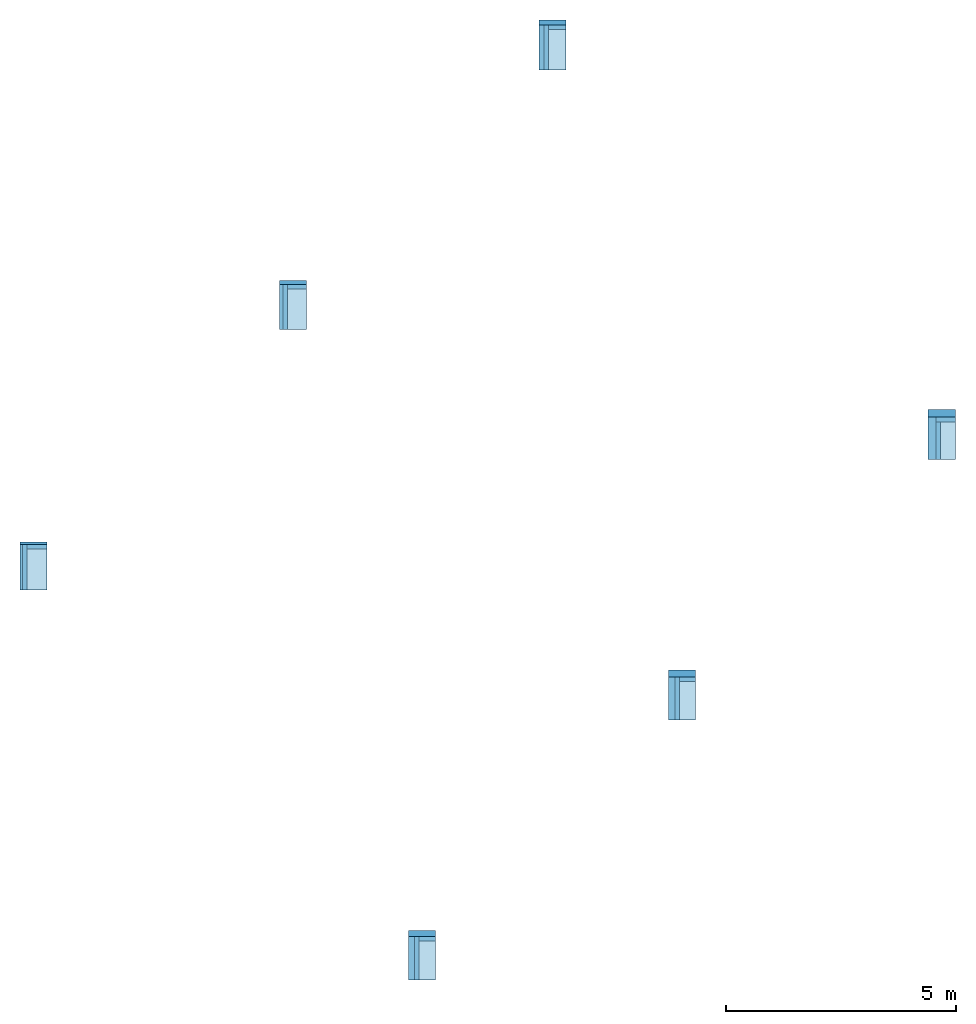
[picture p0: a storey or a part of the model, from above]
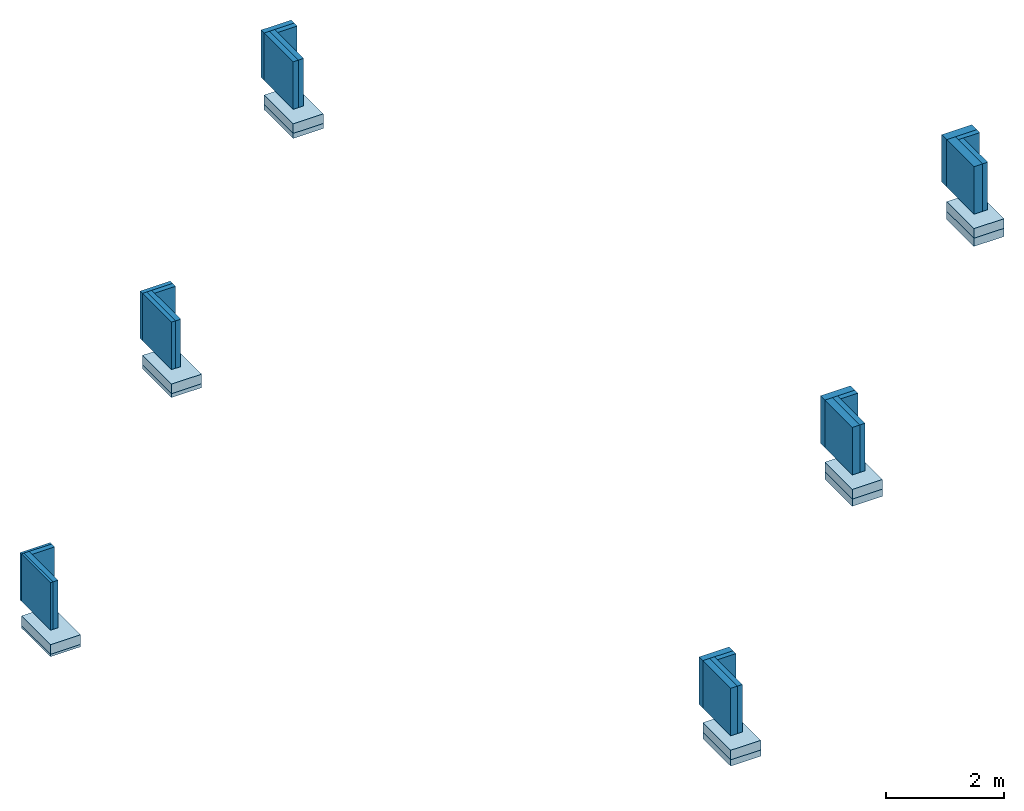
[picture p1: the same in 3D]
Properties of the parts of a building model (IFC2X3), part 2 of 2

# IfcWallStandardCase: Basic Wall:NLRS_42_WA_Heraklith Herafoam 105x985x590mm, Basic Wall:NLRS_42_WA_Heraklith Herafoam 105x985x590mm:925849
Type - Identity Data - Type Image: Raster image: Heraklith Herafoam.jpg; Assembly Code: 42.10; brandweerstand: n.v.t; Description: Herafoam - 105mm; DoP: 4010_HERAFOAM; email: customerservice.nl@knaufinsulation.com; geluidsabsorbtie: 0,30; Manufacturer: Knauf Insulation B.V.; Model: Heraklith® | Herafoam is een houtwolcementpaneel gecombineerd met een PIR-plaat.; NLRS_C_Code_Brandklasse: B-s1,d0; NLRS_C_content_creator: Cadix; NLRS_C_content_versie: V1.0; phone: +31(0)162-421245; product URL: https://heraklith.nl/Heraklith-houtwolcementplaten/herafoam; Type Name: NLRS_42_WA_Heraklith Herafoam 105x985x590mm; URL: www.heraklith.nl; warmteweerstand: 4,10 (m2.K/W)
Type - Other - Category: Walls; Family Name: Basic Wall
Classification: 42.10 (Uniformat)
BaseQuantities - Height: 985 mm; Length: 985 mm; Width: 105 mm; GrossFootprintArea: 0.103425 m2; GrossSideArea: 0.970225 m2; GrossVolume: 0.101874 m3
Constraints - Related to Mass: no; Room Bounding: yes; Base Constraint: Level: 00 begane grond; Base Extension Distance: 0 mm; Base is Attached: no; Base Offset: 0 mm; Location Line: Wall Centerline; Top Constraint: Level: 01 eerste verdieping; Top Extension Distance: 0 mm; Top is Attached: no; Top Offset: 0 mm; Unconnected Height: 985 mm
Dimensions - Area: 0.970225 m2; Length: 985 mm; Volume: 0.101874 m3
Other - Family: Basic Wall: NLRS_42_WA_Heraklith Herafoam 105x985x590mm; Family and Type: Basic Wall: NLRS_42_WA_Heraklith Herafoam 105x985x590mm; Type: Basic Wall: NLRS_42_WA_Heraklith Herafoam 105x985x590mm; Type Id: Basic Wall: NLRS_42_WA_Heraklith Herafoam 105x985x590mm
Phasing - Phase Created: 1
Structural - Enable Analytical Model: no; Structural: no; Structural Usage: Non-bearing
Pset_WallCommon - LoadBearing: no; ExtendToStructure: no; IsExternal: no; Reference: NLRS_42_WA_Heraklith Herafoam 105x985x590mm; ThermalTransmittance: 0.22577 kg/K/s3
Pset_ManufacturerTypeInformation - Manufacturer: Knauf Insulation B.V.

# IfcWallStandardCase: Basic Wall:NLRS_42_WA_Heraklith Herafoam 130x985x590mm, Basic Wall:NLRS_42_WA_Heraklith Herafoam 130x985x590mm:926114
In: 00 begane grond
Type - PredefinedType: STANDARD; Material: Heraklith® | Herafoam - PIR (0,0215) 80 mm, Heraklith® | Herafoam - PIR (0,0275) 40 mm, Heraklith® | Herafoam - Houtwollaag - 985x590mm 10 mm
Type - Analytical Properties - Roughness: 1; Absorptance: 0.1; Heat Transfer Coefficient (U): 0.179673; Thermal mass: 810; Thermal Resistance (R): 5.56566
Type - Construction - Function: Interior; Wrapping at Inserts: Do not wrap; Width: 130 mm
Type - Data - CE-codering: WW-C2 PU-EN13168-L2-W1-S1-T1-P1-CS(10/Y)150-Cl1; Chloride gehalte: Cl1; Druksterkte kPa: 150; gewicht KG/M2: 10.1; kleur: standaard naturel optie: Wit (RAL9003) / RAL; pallet m2: 9.3 m2; panelen per pallet: 16; Randafwerking: Houtwol: Facet: 5mm; Randafwerking: Isolatie: tand en groef; Tolerantie: Breedte (W): (W1) +3/-3; Tolerantie: Dikte (T): (T1) +3/-2; Tolerantie: Haaksheid (S): (S1) ≤4; Tolerantie: Lengte (L): (L2) +3/-5; Tolerantie: Vlakheid (P): (P1) ≤6; vezelbreedte: standaard 2mm optie: 1mm
Type - Graphics - Coarse Scale Fill Color: 0; Coarse Scale Fill Pattern: Solid fill
Type - Identity Data - Type Image: Raster image: Heraklith Herafoam.jpg; Assembly Code: 42.10; brandweerstand: n.v.t; Description: Herafoam - 130mm; DoP: 4010_HERAFOAM; email: customerservice.nl@knaufinsulation.com; geluidsabsorbtie: 0,30; Manufacturer: Knauf Insulation B.V.; Model: Heraklith® | Herafoam is een houtwolcementpaneel gecombineerd met een PIR-plaat.; NLRS_C_Code_Brandklasse: B-s1,d0; NLRS_C_content_creator: Cadix; NLRS_C_content_versie: V1.0; phone: +31(0)162-421245; product URL: https://heraklith.nl/Heraklith-houtwolcementplaten/herafoam; Type Name: NLRS_42_WA_Heraklith Herafoam 130x985x590mm; URL: www.heraklith.nl; warmteweerstand: 5,25 (m2.K/W)
Type - Other - Category: Walls; Family Name: Basic Wall
Classification: 42.10 (Uniformat)
BaseQuantities - Height: 985 mm; Length: 945 mm; Width: 130 mm; GrossFootprintArea: 0.12285 m2; GrossSideArea: 0.930825 m2; GrossVolume: 0.121007 m3
Constraints - Related to Mass: no; Room Bounding: yes; Base Constraint: Level: 00 begane grond; Base Extension Distance: 0 mm; Base is Attached: no; Base Offset: 0 mm; Location Line: Wall Centerline; Top Constraint: Level: 01 eerste verdieping; Top Extension Distance: 0 mm; Top is Attached: no; Top Offset: 0 mm; Unconnected Height: 985 mm
Dimensions - Area: 0.930825 m2; Length: 1010 mm; Volume: 0.121007 m3
Other - Family: Basic Wall: NLRS_42_WA_Heraklith Herafoam 130x985x590mm; Family and Type: Basic Wall: NLRS_42_WA_Heraklith Herafoam 130x985x590mm; Type: Basic Wall: NLRS_42_WA_Heraklith Herafoam 130x985x590mm; Type Id: Basic Wall: NLRS_42_WA_Heraklith Herafoam 130x985x590mm
Phasing - Phase Created: 1
Structural - Enable Analytical Model: no; Structural: no; Structural Usage: Non-bearing
Pset_WallCommon - LoadBearing: no; ExtendToStructure: no; IsExternal: no; Reference: NLRS_42_WA_Heraklith Herafoam 130x985x590mm; ThermalTransmittance: 0.179673 kg/K/s3
Pset_ManufacturerTypeInformation - Manufacturer: Knauf Insulation B.V.

# IfcWallStandardCase: Basic Wall:NLRS_42_WA_Heraklith Herafoam 150x985x590mm, Basic Wall:NLRS_42_WA_Heraklith Herafoam 150x985x590mm:926746
In: 00 begane grond
Type - PredefinedType: STANDARD; Material: Heraklith® | Herafoam - PIR (0,0215) 100 mm, Heraklith® | Herafoam - PIR (0,0275) 40 mm, Heraklith® | Herafoam - Houtwollaag - 985x590mm 10 mm
Type - Analytical Properties - Roughness: 1; Absorptance: 0.1; Heat Transfer Coefficient (U): 0.154446; Thermal mass: 870; Thermal Resistance (R): 6.47475
Type - Construction - Function: Interior; Wrapping at Inserts: Do not wrap; Width: 150 mm
Type - Data - CE-codering: WW-C2 PU-EN13168-L2-W1-S1-T1-P1-CS(10/Y)150-Cl1; Chloride gehalte: Cl1; Druksterkte kPa: 150; gewicht KG/M2: 10.7; kleur: standaard naturel optie: Wit (RAL9003) / RAL; pallet m2: 8.14 m2; panelen per pallet: 14; Randafwerking: Houtwol: Facet: 5mm; Randafwerking: Isolatie: tand en groef; Tolerantie: Breedte (W): (W1) +3/-3; Tolerantie: Dikte (T): (T1) +3/-2; Tolerantie: Haaksheid (S): (S1) ≤4; Tolerantie: Lengte (L): (L2) +3/-5; Tolerantie: Vlakheid (P): (P1) ≤6; vezelbreedte: standaard 2mm optie: 1mm
Type - Graphics - Coarse Scale Fill Color: 0; Coarse Scale Fill Pattern: Solid fill
Type - Identity Data - Type Image: Raster image: Heraklith Herafoam.jpg; Assembly Code: 42.10; brandweerstand: n.v.t; Description: Herafoam - 150mm; DoP: 4010_HERAFOAM; email: customerservice.nl@knaufinsulation.com; geluidsabsorbtie: 0,30; Manufacturer: Knauf Insulation B.V.; Model: Heraklith® | Herafoam is een houtwolcementpaneel gecombineerd met een PIR-plaat.; NLRS_C_Code_Brandklasse: B-s1,d0; NLRS_C_content_creator: Cadix; NLRS_C_content_versie: V1.0; phone: +31(0)162-421245; product URL: https://heraklith.nl/Heraklith-houtwolcementplaten/herafoam; Type Name: NLRS_42_WA_Heraklith Herafoam 150x985x590mm; URL: www.heraklith.nl; warmteweerstand: 6,20 (m2.K/W)
Type - Other - Category: Walls; Family Name: Basic Wall
Classification: 42.10 (Uniformat)
BaseQuantities - Height: 985 mm; Length: 935 mm; Width: 150 mm; GrossFootprintArea: 0.14025 m2; GrossSideArea: 0.920975 m2; GrossVolume: 0.138146 m3
Constraints - Related to Mass: no; Room Bounding: yes; Base Constraint: Level: 00 begane grond; Base Extension Distance: 0 mm; Base is Attached: no; Base Offset: 0 mm; Location Line: Wall Centerline; Top Constraint: Level: 01 eerste verdieping; Top Extension Distance: 0 mm; Top is Attached: no; Top Offset: 0 mm; Unconnected Height: 985 mm
Dimensions - Area: 0.920975 m2; Length: 1010 mm; Volume: 0.138146 m3
Other - Family: Basic Wall: NLRS_42_WA_Heraklith Herafoam 150x985x590mm; Family and Type: Basic Wall: NLRS_42_WA_Heraklith Herafoam 150x985x590mm; Type: Basic Wall: NLRS_42_WA_Heraklith Herafoam 150x985x590mm; Type Id: Basic Wall: NLRS_42_WA_Heraklith Herafoam 150x985x590mm
Phasing - Phase Created: 1
Structural - Enable Analytical Model: no; Structural: no; Structural Usage: Non-bearing
Pset_WallCommon - LoadBearing: no; ExtendToStructure: no; IsExternal: no; Reference: NLRS_42_WA_Heraklith Herafoam 150x985x590mm; ThermalTransmittance: 0.154446 kg/K/s3
Pset_ManufacturerTypeInformation - Manufacturer: Knauf Insulation B.V.

# IfcWallStandardCase: Basic Wall:NLRS_42_WA_Heraklith Herafoam 170x985x590mm, Basic Wall:NLRS_42_WA_Heraklith Herafoam 170x985x590mm:926985
In: 00 begane grond
Type - PredefinedType: STANDARD; Material: Heraklith® | Herafoam - PIR (0,0215) 120 mm, Heraklith® | Herafoam - PIR (0,0275) 40 mm, Heraklith® | Herafoam - Houtwollaag - 985x590mm 10 mm
Type - Analytical Properties - Roughness: 1; Absorptance: 0.1; Heat Transfer Coefficient (U): 0.135431; Thermal mass: 930; Thermal Resistance (R): 7.38384
Type - Construction - Function: Interior; Wrapping at Inserts: Do not wrap; Width: 170 mm
Type - Data - CE-codering: WW-C2 PU-EN13168-L2-W1-S1-T1-P1-CS(10/Y)150-Cl1; Chloride gehalte: Cl1; Druksterkte kPa: 150; gewicht KG/M2: 11.3; kleur: standaard naturel optie: Wit (RAL9003) / RAL; pallet m2: 6.97 m2; panelen per pallet: 12; Randafwerking: Houtwol: Facet: 5mm; Randafwerking: Isolatie: tand en groef; Tolerantie: Breedte (W): (W1) +3/-3; Tolerantie: Dikte (T): (T1) +3/-2; Tolerantie: Haaksheid (S): (S1) ≤4; Tolerantie: Lengte (L): (L2) +3/-5; Tolerantie: Vlakheid (P): (P1) ≤6; vezelbreedte: standaard 2mm optie: 1mm
Type - Graphics - Coarse Scale Fill Color: 0; Coarse Scale Fill Pattern: Solid fill
Type - Identity Data - Type Image: Raster image: Heraklith Herafoam.jpg; Assembly Code: 42.10; brandweerstand: n.v.t; Description: Herafoam - 170mm; DoP: 4010_HERAFOAM; email: customerservice.nl@knaufinsulation.com; geluidsabsorbtie: 0,30; Manufacturer: Knauf Insulation B.V.; Model: Heraklith® | Herafoam is een houtwolcementpaneel gecombineerd met een PIR-plaat.; NLRS_C_Code_Brandklasse: B-s1,d0; NLRS_C_content_creator: Cadix; NLRS_C_content_versie: V1.0; phone: +31(0)162-421245; product URL: https://heraklith.nl/Heraklith-houtwolcementplaten/herafoam; Type Name: NLRS_42_WA_Heraklith Herafoam 170x985x590mm; URL: www.heraklith.nl; warmteweerstand: 7,10 (m2.K/W)
Type - Other - Category: Walls; Family Name: Basic Wall
Classification: 42.10 (Uniformat)
BaseQuantities - Height: 985 mm; Length: 925 mm; Width: 170 mm; GrossFootprintArea: 0.15725 m2; GrossSideArea: 0.911125 m2; GrossVolume: 0.154891 m3
Constraints - Related to Mass: no; Room Bounding: yes; Base Constraint: Level: 00 begane grond; Base Extension Distance: 0 mm; Base is Attached: no; Base Offset: 0 mm; Location Line: Wall Centerline; Top Constraint: Level: 01 eerste verdieping; Top Extension Distance: 0 mm; Top is Attached: no; Top Offset: 0 mm; Unconnected Height: 985 mm
Dimensions - Area: 0.911125 m2; Length: 1010 mm; Volume: 0.154891 m3
Other - Family: Basic Wall: NLRS_42_WA_Heraklith Herafoam 170x985x590mm; Family and Type: Basic Wall: NLRS_42_WA_Heraklith Herafoam 170x985x590mm; Type: Basic Wall: NLRS_42_WA_Heraklith Herafoam 170x985x590mm; Type Id: Basic Wall: NLRS_42_WA_Heraklith Herafoam 170x985x590mm
Phasing - Phase Created: 1
Structural - Enable Analytical Model: no; Structural: no; Structural Usage: Non-bearing
Pset_WallCommon - LoadBearing: no; ExtendToStructure: no; IsExternal: no; Reference: NLRS_42_WA_Heraklith Herafoam 170x985x590mm; ThermalTransmittance: 0.135431 kg/K/s3
Pset_ManufacturerTypeInformation - Manufacturer: Knauf Insulation B.V.

# IfcWallStandardCase: Basic Wall:NLRS_42_WA_Heraklith Herafoam 50x985x590mm, Basic Wall:NLRS_42_WA_Heraklith Herafoam 50x985x590mm:922774
In: 00 begane grond
Type - PredefinedType: STANDARD; Material: Heraklith® | Herafoam - PIR (0,0275) 40 mm, Heraklith® | Herafoam - Houtwollaag - 985x590mm 10 mm
Type - Analytical Properties - Roughness: 1; Absorptance: 0.1; Heat Transfer Coefficient (U): 0.518325; Thermal mass: 570; Thermal Resistance (R): 1.92929
Type - Construction - Function: Interior; Width: 50 mm; Wrapping at Inserts: Do not wrap
Type - Data - CE-codering: WW-C2 PU-EN13168-L2-W1-S1-T1-P1-CS(10/Y)150-Cl1; Chloride gehalte: Cl1; Druksterkte kPa: 150; gewicht KG/M2: 7.3; kleur: standaard naturel optie: Wit (RAL9003) / RAL; pallet m2: 25.57 m2; panelen per pallet: 44; Randafwerking: Houtwol: Facet: 5mm; Randafwerking: Isolatie: tand en groef; Tolerantie: Breedte (W): (W1) +3/-3; Tolerantie: Dikte (T): (T1) +3/-2; Tolerantie: Haaksheid (S): (S1) ≤4; Tolerantie: Lengte (L): (L2) +3/-5; Tolerantie: Vlakheid (P): (P1) ≤6; vezelbreedte: standaard 2mm optie: 1mm
Type - Graphics - Coarse Scale Fill Color: 0; Coarse Scale Fill Pattern: Solid fill
Type - Identity Data - Type Image: Raster image: Heraklith Herafoam.jpg; Assembly Code: 42.10; brandweerstand: n.v.t; Description: Herafoam - 50mm; DoP: 4010_HERAFOAM; email: customerservice.nl@knaufinsulation.com; geluidsabsorbtie: 0,30; Manufacturer: Knauf Insulation B.V.; Model: Heraklith® | Herafoam is een houtwolcementpaneel gecombineerd met een PIR-plaat.; NLRS_C_Code_Brandklasse: B-s1,d0; NLRS_C_content_creator: Cadix; NLRS_C_content_versie: V1.0; phone: +31(0)162-421245; product URL: https://heraklith.nl/Heraklith-houtwolcementplaten/herafoam; Type Name: NLRS_42_WA_Heraklith Herafoam 50x985x590mm; URL: www.heraklith.nl; warmteweerstand: 1,55 (m2.K/W)
Type - Other - Category: Walls; Family Name: Basic Wall
Classification: 42.10 (Uniformat)
BaseQuantities - Height: 985 mm; Length: 985 mm; Width: 50 mm; GrossFootprintArea: 0.04925 m2; GrossSideArea: 0.970225 m2; GrossVolume: 0.0485113 m3
Constraints - Related to Mass: no; Room Bounding: yes; Base Constraint: Level: 00 begane grond; Base Extension Distance: 0 mm; Base is Attached: no; Base Offset: 0 mm; Location Line: Wall Centerline; Top Constraint: Level: 01 eerste verdieping; Top Extension Distance: 0 mm; Top is Attached: no; Top Offset: 0 mm; Unconnected Height: 985 mm
Dimensions - Area: 0.970225 m2; Length: 1010 mm; Volume: 0.0485113 m3
Other - Family: Basic Wall: NLRS_42_WA_Heraklith Herafoam 50x985x590mm; Family and Type: Basic Wall: NLRS_42_WA_Heraklith Herafoam 50x985x590mm; Type: Basic Wall: NLRS_42_WA_Heraklith Herafoam 50x985x590mm; Type Id: Basic Wall: NLRS_42_WA_Heraklith Herafoam 50x985x590mm
Phasing - Phase Created: 1
Structural - Enable Analytical Model: no; Structural: no; Structural Usage: Non-bearing
Pset_WallCommon - Reference: NLRS_42_WA_Heraklith Herafoam 50x985x590mm; LoadBearing: no; ExtendToStructure: no; IsExternal: no; ThermalTransmittance: 0.518325 kg/K/s3
Pset_ManufacturerTypeInformation - Manufacturer: Knauf Insulation B.V.

# IfcWallStandardCase: Basic Wall:NLRS_42_WA_Heraklith Herafoam 80x985x590mm, Basic Wall:NLRS_42_WA_Heraklith Herafoam 80x985x590mm:925193
In: 00 begane grond
Type - PredefinedType: STANDARD; Material: Heraklith® | Herafoam - PIR (0,0222) 30 mm, Heraklith® | Herafoam - PIR (0,0275) 40 mm, Heraklith® | Herafoam - Houtwollaag - 985x590mm 10 mm
Type - Analytical Properties - Roughness: 1; Absorptance: 0.1; Heat Transfer Coefficient (U): 0.303681; Thermal mass: 660; Thermal Resistance (R): 3.29293
Type - Construction - Function: Interior; Wrapping at Inserts: Do not wrap; Width: 80 mm
Type - Data - CE-codering: WW-C2 PU-EN13168-L2-W1-S1-T1-P1-CS(10/Y)150-Cl1; Chloride gehalte: Cl1; Druksterkte kPa: 150; gewicht KG/M2: 8.6; kleur: standaard naturel optie: Wit (RAL9003) / RAL; pallet m2: 15.11 m2; panelen per pallet: 26; Randafwerking: Houtwol: Facet: 5mm; Randafwerking: Isolatie: tand en groef; Tolerantie: Breedte (W): (W1) +3/-3; Tolerantie: Dikte (T): (T1) +3/-2; Tolerantie: Haaksheid (S): (S1) ≤4; Tolerantie: Lengte (L): (L2) +3/-5; Tolerantie: Vlakheid (P): (P1) ≤6; vezelbreedte: standaard 2mm optie: 1mm
Type - Graphics - Coarse Scale Fill Color: 0; Coarse Scale Fill Pattern: Solid fill
Type - Identity Data - Type Image: Raster image: Heraklith Herafoam.jpg; Assembly Code: 42.10; brandweerstand: n.v.t; Description: Herafoam - 80mm; DoP: 4010_HERAFOAM; email: customerservice.nl@knaufinsulation.com; geluidsabsorbtie: 0,30; Manufacturer: Knauf Insulation B.V.; Model: Heraklith® | Herafoam is een houtwolcementpaneel gecombineerd met een PIR-plaat.; NLRS_C_Code_Brandklasse: B-s1,d0; NLRS_C_content_creator: Cadix; NLRS_C_content_versie: V1.0; phone: +31(0)162-421245; product URL: https://heraklith.nl/Heraklith-houtwolcementplaten/herafoam; Type Name: NLRS_42_WA_Heraklith Herafoam 80x985x590mm; URL: www.heraklith.nl; warmteweerstand: 2,90 (m2.K/W)
Type - Other - Category: Walls; Family Name: Basic Wall
Classification: 42.10 (Uniformat)
BaseQuantities - Height: 985 mm; Length: 985 mm; Width: 80 mm; GrossFootprintArea: 0.0788 m2; GrossSideArea: 0.970225 m2; GrossVolume: 0.077618 m3
Constraints - Related to Mass: no; Room Bounding: yes; Base Constraint: Level: 00 begane grond; Base Extension Distance: 0 mm; Base is Attached: no; Base Offset: 0 mm; Location Line: Wall Centerline; Top Constraint: Level: 01 eerste verdieping; Top Extension Distance: 0 mm; Top is Attached: no; Top Offset: 0 mm; Unconnected Height: 985 mm
Dimensions - Area: 0.970225 m2; Length: 985 mm; Volume: 0.077618 m3
Other - Family: Basic Wall: NLRS_42_WA_Heraklith Herafoam 80x985x590mm; Family and Type: Basic Wall: NLRS_42_WA_Heraklith Herafoam 80x985x590mm; Type: Basic Wall: NLRS_42_WA_Heraklith Herafoam 80x985x590mm; Type Id: Basic Wall: NLRS_42_WA_Heraklith Herafoam 80x985x590mm
Phasing - Phase Created: 1
Structural - Enable Analytical Model: no; Structural: no; Structural Usage: Non-bearing
Pset_WallCommon - LoadBearing: no; ExtendToStructure: no; IsExternal: no; Reference: NLRS_42_WA_Heraklith Herafoam 80x985x590mm; ThermalTransmittance: 0.303681 kg/K/s3
Pset_ManufacturerTypeInformation - Manufacturer: Knauf Insulation B.V.
